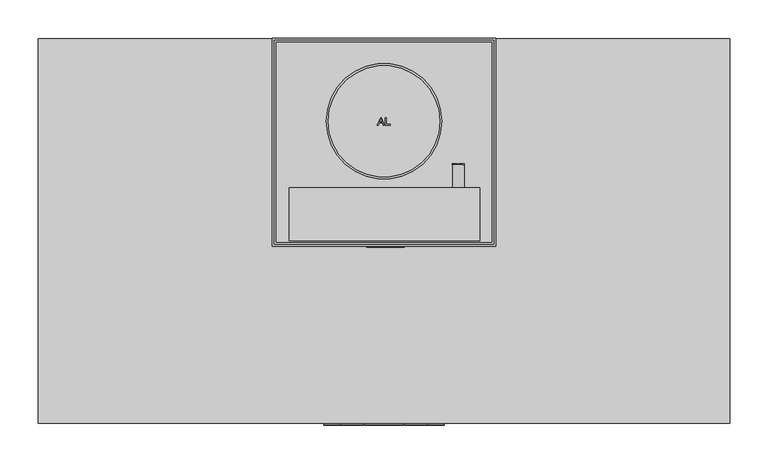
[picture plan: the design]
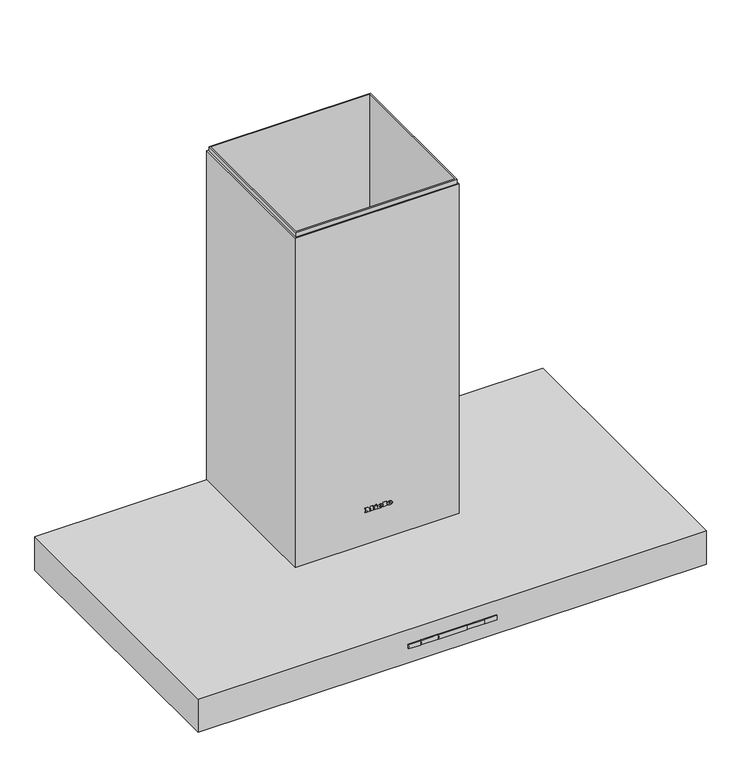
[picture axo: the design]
"""IFC4 building model written with IfcOpenShell, lengths in millimetres: proxy geometry."""

from ifc_helpers import new_model, si_unit, point, frame, frame_2d, origin, place, context, project, spatial, polyline, circle_curve, ellipse_curve, trimmed, segment, composite_curve, outline, extrude, faceted_brep, source, transform, mapped, element, save
from ifc_brep_helpers import plane_surface, cylinder_surface, revolved_surface, extruded_surface, advanced_brep


def specialty_equipment_3feef1e1(model_context):
    return source(origin(), model_context, "Body", "SolidModel", [
        advanced_brep(
        [(-27.2862224, -435.7, 0.8), (27.2862224, -435.7, 0.8), (29.0, -435.7, 2.0), (-29.0, -435.7, 2.0), (0.0, -435.7, 0.8), (0.0, -435.7, 2.0)],
        [
            (0, 1, circle_curve(frame((0.0, -435.7, 0.8), z_axis=(0.0, 0.0, 1.0), x_axis=(1.0, 0.0, 0.0)), 27.2862224)),
            (1, 2),
            (2, 3, circle_curve(frame((0.0, -435.7, 2.0), z_axis=(0.0, 0.0, -1.0), x_axis=(1.0, 0.0, 0.0)), 29.0)),
            (3, 0),
            (1, 0, circle_curve(frame((0.0, -435.7, 0.8), z_axis=(0.0, 0.0, 1.0), x_axis=(1.0, 0.0, 0.0)), 27.2862224)),
            (3, 2, circle_curve(frame((0.0, -435.7, 2.0), z_axis=(0.0, 0.0, -1.0), x_axis=(1.0, 0.0, 0.0)), 29.0)),
            (4, 1),
            (0, 4),
            (2, 5),
            (5, 3),
        ],
        [
            revolved_surface(polyline([(29.0, -435.7, 2.0), (27.2862224, -435.7, 0.8)]), (0.0, -435.7, 1830.7560264), (0.0, 0.0, -1.0)),
            plane_surface(frame((0.0, -435.7, 0.8), z_axis=(0.0, 0.0, -1.0), x_axis=(1.0, 0.0, 0.0))),
            plane_surface(frame((0.0, -435.7, 2.0), z_axis=(0.0, 0.0, 1.0), x_axis=(1.0, 0.0, 0.0))),
        ],
        [
            (0, [[1, 2, 3, 4]]),
            (0, [[5, -4, 6, -2]]),
            (1, [[7, -1, 8]]),
            (1, [[-8, -5, -7]]),
            (2, [[-3, 9, 10]]),
            (2, [[-6, -10, -9]]),
        ],
    ),
        advanced_brep(
        [(-296.5433287, -435.7, 0.8), (-243.4566713, -435.7, 0.8), (-240.883263, -435.7, 2.0), (-299.116737, -435.7, 2.0), (-270.0, -435.7, 0.8), (-270.0, -435.7, 2.0)],
        [
            (0, 1, circle_curve(frame((-270.0, -435.7, 0.8), z_axis=(0.0, 0.0, 1.0), x_axis=(1.0, 0.0, 0.0)), 26.5433287)),
            (1, 2),
            (2, 3, circle_curve(frame((-270.0, -435.7, 2.0), z_axis=(0.0, 0.0, -1.0), x_axis=(1.0, 0.0, 0.0)), 29.116737)),
            (3, 0),
            (1, 0, circle_curve(frame((-270.0, -435.7, 0.8), z_axis=(0.0, 0.0, 1.0), x_axis=(1.0, 0.0, 0.0)), 26.5433287)),
            (3, 2, circle_curve(frame((-270.0, -435.7, 2.0), z_axis=(0.0, 0.0, -1.0), x_axis=(1.0, 0.0, 0.0)), 29.116737)),
            (0, 4),
            (4, 1),
            (2, 5),
            (5, 3),
        ],
        [
            revolved_surface(polyline([(-240.883263, -435.7, 2.0), (-243.4566713, -435.7, 0.8)]), (-270.0, -435.7, 2240.4), (0.0, 0.0, -1.0)),
            plane_surface(frame((-270.0, -435.7, 0.8), z_axis=(0.0, 0.0, -1.0), x_axis=(1.0, 0.0, 0.0))),
            plane_surface(frame((-270.0, -435.7, 2.0), z_axis=(0.0, 0.0, 1.0), x_axis=(1.0, 0.0, 0.0))),
        ],
        [
            (0, [[1, 2, 3, 4]]),
            (0, [[-2, 5, -4, 6]]),
            (1, [[-1, 7, 8]]),
            (1, [[-5, -8, -7]]),
            (2, [[-3, 9, 10]]),
            (2, [[-6, -10, -9]]),
        ],
    ),
        advanced_brep(
        [(243.4566713, -435.7, 0.8), (296.5433287, -435.7, 0.8), (299.116737, -435.7, 2.0), (240.883263, -435.7, 2.0), (270.0, -435.7, 0.8), (270.0, -435.7, 2.0)],
        [
            (0, 1, circle_curve(frame((270.0, -435.7, 0.8), z_axis=(0.0, 0.0, 1.0), x_axis=(1.0, 0.0, 0.0)), 26.5433287)),
            (1, 2),
            (2, 3, circle_curve(frame((270.0, -435.7, 2.0), z_axis=(0.0, 0.0, -1.0), x_axis=(1.0, 0.0, 0.0)), 29.116737)),
            (3, 0),
            (1, 0, circle_curve(frame((270.0, -435.7, 0.8), z_axis=(0.0, 0.0, 1.0), x_axis=(1.0, 0.0, 0.0)), 26.5433287)),
            (3, 2, circle_curve(frame((270.0, -435.7, 2.0), z_axis=(0.0, 0.0, -1.0), x_axis=(1.0, 0.0, 0.0)), 29.116737)),
            (0, 4),
            (4, 1),
            (2, 5),
            (5, 3),
        ],
        [
            revolved_surface(polyline([(299.116737, -435.7, 2.0), (296.5433287, -435.7, 0.8)]), (270.0, -435.7, 2240.4), (0.0, 0.0, -1.0)),
            plane_surface(frame((270.0, -435.7, 0.8), z_axis=(0.0, 0.0, -1.0), x_axis=(1.0, 0.0, 0.0))),
            plane_surface(frame((270.0, -435.7, 2.0), z_axis=(0.0, 0.0, 1.0), x_axis=(1.0, 0.0, 0.0))),
        ],
        [
            (0, [[1, 2, 3, 4]]),
            (0, [[-2, 5, -4, 6]]),
            (1, [[-1, 7, 8]]),
            (1, [[-5, -8, -7]]),
            (2, [[-3, 9, 10]]),
            (2, [[-6, -10, -9]]),
        ],
    ),
        extrude(outline(polyline([(134.3333333, -34.0), (134.3333333, -391.0), (-134.3333333, -391.0), (-134.3333333, -34.0), (134.3333333, -34.0)])), frame((0.0, 0.0, 6.5), z_axis=(0.0, 0.0, 1.0), x_axis=(1.0, 0.0, 0.0)), (0.0, 0.0, 1.0), 6.0),
        extrude(outline(polyline([(143.3333333, -25.0), (143.3333333, -400.0), (-143.3333333, -400.0), (-143.3333333, -25.0), (143.3333333, -25.0)]), holes=[polyline([(134.3333333, -34.0), (-134.3333333, -34.0), (-134.3333333, -391.0), (134.3333333, -391.0), (134.3333333, -34.0)])]), frame((0.0, 0.0, 5.0), z_axis=(0.0, 0.0, 1.0), x_axis=(1.0, 0.0, 0.0)), (0.0, 0.0, 1.0), 9.0),
        extrude(outline(polyline([(152.3333333, -34.0), (421.0, -34.0), (421.0, -391.0), (152.3333333, -391.0), (152.3333333, -34.0)])), frame((0.0, 0.0, 6.5), z_axis=(0.0, 0.0, 1.0), x_axis=(1.0, 0.0, 0.0)), (0.0, 0.0, 1.0), 6.0),
        extrude(outline(polyline([(143.3333333, -25.0), (430.0, -25.0), (430.0, -400.0), (143.3333333, -400.0), (143.3333333, -25.0)]), holes=[polyline([(152.3333333, -34.0), (152.3333333, -391.0), (421.0, -391.0), (421.0, -34.0), (152.3333333, -34.0)])]), frame((0.0, 0.0, 5.0), z_axis=(0.0, 0.0, 1.0), x_axis=(1.0, 0.0, 0.0)), (0.0, 0.0, 1.0), 9.0),
        extrude(outline(polyline([(-152.3333333, -34.0), (-152.3333333, -391.0), (-421.0, -391.0), (-421.0, -34.0), (-152.3333333, -34.0)])), frame((0.0, 0.0, 6.5), z_axis=(0.0, 0.0, 1.0), x_axis=(1.0, 0.0, 0.0)), (0.0, 0.0, 1.0), 6.0),
        extrude(outline(polyline([(-143.3333333, -25.0), (-143.3333333, -400.0), (-430.0, -400.0), (-430.0, -25.0), (-143.3333333, -25.0)]), holes=[polyline([(-152.3333333, -34.0), (-421.0, -34.0), (-421.0, -391.0), (-152.3333333, -391.0), (-152.3333333, -34.0)])]), frame((0.0, 0.0, 5.0), z_axis=(0.0, 0.0, 1.0), x_axis=(1.0, 0.0, 0.0)), (0.0, 0.0, 1.0), 9.0),
        extrude(outline(polyline([(16.5, -348.0), (16.5, -391.0), (-16.5, -391.0), (-16.5, -348.0), (16.5, -348.0)]), holes=[polyline([(10.0, -354.5), (-10.0, -354.5), (-10.0, -363.5), (10.0, -363.5), (10.0, -354.5)])]), frame((0.0, 0.0, 5.0), z_axis=(0.0, 0.0, 1.0), x_axis=(1.0, 0.0, 0.0)), (0.0, 0.0, 1.0), 1.5),
        extrude(outline(polyline([(270.1666667, -348.0), (303.1666667, -348.0), (303.1666667, -391.0), (270.1666667, -391.0), (270.1666667, -348.0)]), holes=[polyline([(276.6666667, -354.5), (276.6666667, -363.5), (296.4380995, -363.5), (296.4380995, -354.5), (276.6666667, -354.5)])]), frame((0.0, 0.0, 5.0), z_axis=(0.0, 0.0, 1.0), x_axis=(1.0, 0.0, 0.0)), (0.0, 0.0, 1.0), 1.5),
        extrude(outline(polyline([(-270.1666667, -348.0), (-270.1666667, -391.0), (-303.1666667, -391.0), (-303.1666667, -348.0), (-270.1666667, -348.0)]), holes=[polyline([(-276.6666667, -354.5), (-296.6666667, -354.5), (-296.6666667, -363.5), (-276.6666667, -363.5), (-276.6666667, -354.5)])]), frame((0.0, 0.0, 5.0), z_axis=(0.0, 0.0, 1.0), x_axis=(1.0, 0.0, 0.0)), (0.0, 0.0, 1.0), 1.5),
        faceted_brep([(-142.5, -267.5, 685.0), (142.5, -267.5, 685.0), (142.5, -2.5, 685.0), (-142.5, -2.5, 685.0), (140.0, -5.0, 685.0), (140.0, -265.0, 685.0), (-140.0, -265.0, 685.0), (-140.0, -5.0, 685.0), (-142.5, -267.5, 210.0), (-142.5, -2.5, 210.0), (142.5, -2.5, 210.0), (142.5, -267.5, 210.0), (140.0, -5.0, 210.0), (-140.0, -5.0, 210.0), (-140.0, -265.0, 210.0), (140.0, -265.0, 210.0), (-142.5, -247.0, 245.0), (-142.5, -236.4, 245.0), (-142.5, -236.4, 345.0), (-142.5, -247.0, 345.0), (-142.5, -225.8, 245.0), (-142.5, -215.2, 245.0), (-142.5, -215.2, 345.0), (-142.5, -225.8, 345.0), (-142.5, -204.6, 245.0), (-142.5, -194.0, 245.0), (-142.5, -194.0, 345.0), (-142.5, -204.6, 345.0), (-142.5, -183.4, 245.0), (-142.5, -172.8, 245.0), (-142.5, -172.8, 345.0), (-142.5, -183.4, 345.0), (-142.5, -162.2, 245.0), (-142.5, -151.6, 245.0), (-142.5, -151.6, 345.0), (-142.5, -162.2, 345.0), (-142.5, -141.0, 245.0), (-142.5, -129.0, 245.0), (-142.5, -129.0, 345.0), (-142.5, -141.0, 345.0), (-142.5, -118.4, 245.0), (-142.5, -107.8, 245.0), (-142.5, -107.8, 345.0), (-142.5, -118.4, 345.0), (-142.5, -97.2, 245.0), (-142.5, -86.6, 245.0), (-142.5, -86.6, 345.0), (-142.5, -97.2, 345.0), (-142.5, -76.0, 245.0), (-142.5, -65.4, 245.0), (-142.5, -65.4, 345.0), (-142.5, -76.0, 345.0), (-142.5, -54.8, 245.0), (-142.5, -44.2, 245.0), (-142.5, -44.2, 345.0), (-142.5, -54.8, 345.0), (-142.5, -33.6, 245.0), (-142.5, -23.0, 245.0), (-142.5, -23.0, 345.0), (-142.5, -33.6, 345.0), (121.0, -265.0, 245.0), (121.0, -265.0, 345.0), (109.0, -265.0, 345.0), (109.0, -265.0, 245.0), (-121.0, -265.0, 345.0), (-121.0, -265.0, 245.0), (-109.0, -265.0, 245.0), (-109.0, -265.0, 345.0), (-86.0, -265.0, 345.0), (-97.5, -265.0, 345.0), (-97.5, -265.0, 245.0), (-86.0, -265.0, 245.0), (-63.0, -265.0, 345.0), (-74.5, -265.0, 345.0), (-74.5, -265.0, 245.0), (-63.0, -265.0, 245.0), (-40.0, -265.0, 345.0), (-51.5, -265.0, 345.0), (-51.5, -265.0, 245.0), (-40.0, -265.0, 245.0), (-17.0, -265.0, 345.0), (-28.5, -265.0, 345.0), (-28.5, -265.0, 245.0), (-17.0, -265.0, 245.0), (5.5, -265.0, 345.0), (-5.5, -265.0, 345.0), (-5.5, -265.0, 245.0), (5.5, -265.0, 245.0), (28.5, -265.0, 345.0), (17.0, -265.0, 345.0), (17.0, -265.0, 245.0), (28.5, -265.0, 245.0), (51.5, -265.0, 345.0), (40.0, -265.0, 345.0), (40.0, -265.0, 245.0), (51.5, -265.0, 245.0), (74.5, -265.0, 345.0), (63.0, -265.0, 345.0), (63.0, -265.0, 245.0), (74.5, -265.0, 245.0), (97.5, -265.0, 345.0), (86.0, -265.0, 345.0), (86.0, -265.0, 245.0), (97.5, -265.0, 245.0), (-140.0, -236.4, 245.0), (-140.0, -247.0, 245.0), (-140.0, -247.0, 345.0), (-140.0, -236.4, 345.0), (-140.0, -215.2, 245.0), (-140.0, -225.8, 245.0), (-140.0, -225.8, 345.0), (-140.0, -215.2, 345.0), (-140.0, -194.0, 245.0), (-140.0, -204.6, 245.0), (-140.0, -204.6, 345.0), (-140.0, -194.0, 345.0), (-140.0, -172.8, 245.0), (-140.0, -183.4, 245.0), (-140.0, -183.4, 345.0), (-140.0, -172.8, 345.0), (-140.0, -151.6, 245.0), (-140.0, -162.2, 245.0), (-140.0, -162.2, 345.0), (-140.0, -151.6, 345.0), (-140.0, -129.0, 245.0), (-140.0, -141.0, 245.0), (-140.0, -141.0, 345.0), (-140.0, -129.0, 345.0), (-140.0, -107.8, 245.0), (-140.0, -118.4, 245.0), (-140.0, -118.4, 345.0), (-140.0, -107.8, 345.0), (-140.0, -86.6, 245.0), (-140.0, -97.2, 245.0), (-140.0, -97.2, 345.0), (-140.0, -86.6, 345.0), (-140.0, -65.4, 245.0), (-140.0, -76.0, 245.0), (-140.0, -76.0, 345.0), (-140.0, -65.4, 345.0), (-140.0, -44.2, 245.0), (-140.0, -54.8, 245.0), (-140.0, -54.8, 345.0), (-140.0, -44.2, 345.0), (-140.0, -23.0, 245.0), (-140.0, -33.6, 245.0), (-140.0, -33.6, 345.0), (-140.0, -23.0, 345.0), (140.0, -247.0, 345.0), (140.0, -247.0, 245.0), (140.0, -236.4, 245.0), (140.0, -236.4, 345.0), (140.0, -23.0, 245.0), (140.0, -23.0, 345.0), (140.0, -33.6, 345.0), (140.0, -33.6, 245.0), (140.0, -225.8, 345.0), (140.0, -225.8, 245.0), (140.0, -215.2, 245.0), (140.0, -215.2, 345.0), (140.0, -204.6, 345.0), (140.0, -204.6, 245.0), (140.0, -194.0, 245.0), (140.0, -194.0, 345.0), (140.0, -183.4, 345.0), (140.0, -183.4, 245.0), (140.0, -172.8, 245.0), (140.0, -172.8, 345.0), (140.0, -162.2, 345.0), (140.0, -162.2, 245.0), (140.0, -151.6, 245.0), (140.0, -151.6, 345.0), (140.0, -44.2, 245.0), (140.0, -44.2, 345.0), (140.0, -54.8, 345.0), (140.0, -54.8, 245.0), (140.0, -65.4, 245.0), (140.0, -65.4, 345.0), (140.0, -76.0, 345.0), (140.0, -76.0, 245.0), (140.0, -86.6, 245.0), (140.0, -86.6, 345.0), (140.0, -97.2, 345.0), (140.0, -97.2, 245.0), (140.0, -107.8, 245.0), (140.0, -107.8, 345.0), (140.0, -118.4, 345.0), (140.0, -118.4, 245.0), (140.0, -129.0, 245.0), (140.0, -129.0, 345.0), (140.0, -141.0, 345.0), (140.0, -141.0, 245.0), (142.5, -23.0, 345.0), (142.5, -23.0, 245.0), (142.5, -33.6, 245.0), (142.5, -33.6, 345.0), (142.5, -247.0, 245.0), (142.5, -247.0, 345.0), (142.5, -236.4, 345.0), (142.5, -236.4, 245.0), (142.5, -225.8, 245.0), (142.5, -225.8, 345.0), (142.5, -215.2, 345.0), (142.5, -215.2, 245.0), (142.5, -204.6, 245.0), (142.5, -204.6, 345.0), (142.5, -194.0, 345.0), (142.5, -194.0, 245.0), (142.5, -183.4, 245.0), (142.5, -183.4, 345.0), (142.5, -172.8, 345.0), (142.5, -172.8, 245.0), (142.5, -162.2, 245.0), (142.5, -162.2, 345.0), (142.5, -151.6, 345.0), (142.5, -151.6, 245.0), (142.5, -44.2, 345.0), (142.5, -44.2, 245.0), (142.5, -54.8, 245.0), (142.5, -54.8, 345.0), (142.5, -65.4, 345.0), (142.5, -65.4, 245.0), (142.5, -76.0, 245.0), (142.5, -76.0, 345.0), (142.5, -86.6, 345.0), (142.5, -86.6, 245.0), (142.5, -97.2, 245.0), (142.5, -97.2, 345.0), (142.5, -107.8, 345.0), (142.5, -107.8, 245.0), (142.5, -118.4, 245.0), (142.5, -118.4, 345.0), (142.5, -129.0, 345.0), (142.5, -129.0, 245.0), (142.5, -141.0, 245.0), (142.5, -141.0, 345.0), (121.0, -267.5, 345.0), (121.0, -267.5, 245.0), (109.0, -267.5, 245.0), (109.0, -267.5, 345.0), (-121.0, -267.5, 245.0), (-121.0, -267.5, 345.0), (-109.0, -267.5, 345.0), (-109.0, -267.5, 245.0), (-97.5, -267.5, 345.0), (-86.0, -267.5, 345.0), (-86.0, -267.5, 245.0), (-97.5, -267.5, 245.0), (-74.5, -267.5, 345.0), (-63.0, -267.5, 345.0), (-63.0, -267.5, 245.0), (-74.5, -267.5, 245.0), (-51.5, -267.5, 345.0), (-40.0, -267.5, 345.0), (-40.0, -267.5, 245.0), (-51.5, -267.5, 245.0), (-28.5, -267.5, 345.0), (-17.0, -267.5, 345.0), (-17.0, -267.5, 245.0), (-28.5, -267.5, 245.0), (-5.5, -267.5, 345.0), (5.5, -267.5, 345.0), (5.5, -267.5, 245.0), (-5.5, -267.5, 245.0), (17.0, -267.5, 345.0), (28.5, -267.5, 345.0), (28.5, -267.5, 245.0), (17.0, -267.5, 245.0), (40.0, -267.5, 345.0), (51.5, -267.5, 345.0), (51.5, -267.5, 245.0), (40.0, -267.5, 245.0), (63.0, -267.5, 345.0), (74.5, -267.5, 345.0), (74.5, -267.5, 245.0), (63.0, -267.5, 245.0), (86.0, -267.5, 345.0), (97.5, -267.5, 345.0), (97.5, -267.5, 245.0), (86.0, -267.5, 245.0)], [[[0, 1, 2, 3], [4, 5, 6, 7]], [[8, 9, 10, 11], [12, 13, 14, 15]], [[0, 3, 9, 8], [16, 17, 18, 19], [20, 21, 22, 23], [24, 25, 26, 27], [28, 29, 30, 31], [32, 33, 34, 35], [36, 37, 38, 39], [40, 41, 42, 43], [44, 45, 46, 47], [48, 49, 50, 51], [52, 53, 54, 55], [56, 57, 58, 59]], [[6, 5, 15, 14], [60, 61, 62, 63], [64, 65, 66, 67], [68, 69, 70, 71], [72, 73, 74, 75], [76, 77, 78, 79], [80, 81, 82, 83], [84, 85, 86, 87], [88, 89, 90, 91], [92, 93, 94, 95], [96, 97, 98, 99], [100, 101, 102, 103]], [[7, 6, 14, 13], [104, 105, 106, 107], [108, 109, 110, 111], [112, 113, 114, 115], [116, 117, 118, 119], [120, 121, 122, 123], [124, 125, 126, 127], [128, 129, 130, 131], [132, 133, 134, 135], [136, 137, 138, 139], [140, 141, 142, 143], [144, 145, 146, 147]], [[5, 4, 12, 15], [148, 149, 150, 151], [152, 153, 154, 155], [156, 157, 158, 159], [160, 161, 162, 163], [164, 165, 166, 167], [168, 169, 170, 171], [172, 173, 174, 175], [176, 177, 178, 179], [180, 181, 182, 183], [184, 185, 186, 187], [188, 189, 190, 191]], [[2, 1, 11, 10], [192, 193, 194, 195], [196, 197, 198, 199], [200, 201, 202, 203], [204, 205, 206, 207], [208, 209, 210, 211], [212, 213, 214, 215], [216, 217, 218, 219], [220, 221, 222, 223], [224, 225, 226, 227], [228, 229, 230, 231], [232, 233, 234, 235]], [[1, 0, 8, 11], [236, 237, 238, 239], [240, 241, 242, 243], [244, 245, 246, 247], [248, 249, 250, 251], [252, 253, 254, 255], [256, 257, 258, 259], [260, 261, 262, 263], [264, 265, 266, 267], [268, 269, 270, 271], [272, 273, 274, 275], [276, 277, 278, 279]], [[3, 2, 10, 9]], [[4, 7, 13, 12]], [[60, 237, 236, 61]], [[64, 241, 240, 65]], [[196, 149, 148, 197]], [[192, 153, 152, 193]], [[149, 196, 199, 150]], [[150, 199, 198, 151]], [[197, 148, 151, 198]], [[153, 192, 195, 154]], [[154, 195, 194, 155]], [[193, 152, 155, 194]], [[200, 157, 156, 201]], [[157, 200, 203, 158]], [[158, 203, 202, 159]], [[201, 156, 159, 202]], [[204, 161, 160, 205]], [[161, 204, 207, 162]], [[162, 207, 206, 163]], [[205, 160, 163, 206]], [[208, 165, 164, 209]], [[165, 208, 211, 166]], [[166, 211, 210, 167]], [[209, 164, 167, 210]], [[212, 169, 168, 213]], [[169, 212, 215, 170]], [[170, 215, 214, 171]], [[213, 168, 171, 214]], [[216, 173, 172, 217]], [[173, 216, 219, 174]], [[174, 219, 218, 175]], [[217, 172, 175, 218]], [[220, 177, 176, 221]], [[177, 220, 223, 178]], [[178, 223, 222, 179]], [[221, 176, 179, 222]], [[224, 181, 180, 225]], [[181, 224, 227, 182]], [[182, 227, 226, 183]], [[225, 180, 183, 226]], [[228, 185, 184, 229]], [[185, 228, 231, 186]], [[186, 231, 230, 187]], [[229, 184, 187, 230]], [[232, 189, 188, 233]], [[189, 232, 235, 190]], [[190, 235, 234, 191]], [[233, 188, 191, 234]], [[104, 17, 16, 105]], [[17, 104, 107, 18]], [[18, 107, 106, 19]], [[105, 16, 19, 106]], [[108, 21, 20, 109]], [[21, 108, 111, 22]], [[22, 111, 110, 23]], [[109, 20, 23, 110]], [[112, 25, 24, 113]], [[25, 112, 115, 26]], [[26, 115, 114, 27]], [[113, 24, 27, 114]], [[116, 29, 28, 117]], [[29, 116, 119, 30]], [[30, 119, 118, 31]], [[117, 28, 31, 118]], [[120, 33, 32, 121]], [[33, 120, 123, 34]], [[34, 123, 122, 35]], [[121, 32, 35, 122]], [[124, 37, 36, 125]], [[37, 124, 127, 38]], [[38, 127, 126, 39]], [[125, 36, 39, 126]], [[128, 41, 40, 129]], [[41, 128, 131, 42]], [[42, 131, 130, 43]], [[129, 40, 43, 130]], [[132, 45, 44, 133]], [[45, 132, 135, 46]], [[46, 135, 134, 47]], [[133, 44, 47, 134]], [[136, 49, 48, 137]], [[49, 136, 139, 50]], [[50, 139, 138, 51]], [[137, 48, 51, 138]], [[140, 53, 52, 141]], [[53, 140, 143, 54]], [[54, 143, 142, 55]], [[141, 52, 55, 142]], [[144, 57, 56, 145]], [[57, 144, 147, 58]], [[58, 147, 146, 59]], [[145, 56, 59, 146]], [[241, 64, 67, 242]], [[242, 67, 66, 243]], [[65, 240, 243, 66]], [[237, 60, 63, 238]], [[238, 63, 62, 239]], [[61, 236, 239, 62]], [[68, 245, 244, 69]], [[245, 68, 71, 246]], [[246, 71, 70, 247]], [[69, 244, 247, 70]], [[72, 249, 248, 73]], [[249, 72, 75, 250]], [[250, 75, 74, 251]], [[73, 248, 251, 74]], [[76, 253, 252, 77]], [[253, 76, 79, 254]], [[254, 79, 78, 255]], [[77, 252, 255, 78]], [[80, 257, 256, 81]], [[257, 80, 83, 258]], [[258, 83, 82, 259]], [[81, 256, 259, 82]], [[84, 261, 260, 85]], [[261, 84, 87, 262]], [[262, 87, 86, 263]], [[85, 260, 263, 86]], [[88, 265, 264, 89]], [[265, 88, 91, 266]], [[266, 91, 90, 267]], [[89, 264, 267, 90]], [[92, 269, 268, 93]], [[269, 92, 95, 270]], [[270, 95, 94, 271]], [[93, 268, 271, 94]], [[96, 273, 272, 97]], [[273, 96, 99, 274]], [[274, 99, 98, 275]], [[97, 272, 275, 98]], [[100, 277, 276, 101]], [[277, 100, 103, 278]], [[278, 103, 102, 279]], [[101, 276, 279, 102]]]),
        extrude(outline(polyline([(145.0, 0.0), (145.0, -270.0), (-145.0, -270.0), (-145.0, 0.0), (145.0, 0.0)]), holes=[polyline([(-142.5, -2.5), (-142.5, -267.5), (142.5, -267.5), (142.5, -2.5), (-142.5, -2.5)])]), frame((0.0, 0.0, 62.0), z_axis=(0.0, 0.0, 1.0), x_axis=(1.0, 0.0, 0.0)), (0.0, 0.0, 1.0), 615.0),
        advanced_brep(
        [(21.104, -271.0, 123.896), (21.104, -271.0, 124.704), (26.456, -271.0, 124.704), (17.144, -271.0, 124.704), (19.344, -271.0, 122.0), (26.32, -271.0, 123.896), (23.904, -271.0, 123.896), (22.0, -271.0, 123.0), (21.104, -271.0, 125.728), (21.104, -271.0, 126.6), (22.472, -271.0, 126.6), (22.472, -271.0, 125.728), (21.104, -270.0, 123.896), (22.0, -270.0, 123.0), (23.904, -270.0, 123.896), (26.32, -270.0, 123.896), (19.344, -270.0, 122.0), (17.144, -270.0, 124.704), (26.456, -270.0, 124.704), (21.104, -270.0, 124.704), (21.104, -270.0, 125.728), (22.472, -270.0, 125.728), (22.472, -270.0, 126.6), (21.104, -270.0, 126.6)],
        [
            (0, 1),
            (1, 2),
            (2, 3, ellipse_curve(frame((21.8, -271.0, 124.704), z_axis=(0.0, -1.0, -1.2192856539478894e-11), x_axis=(-1.0, 0.0, 0.0)), 4.656, 3.848)),
            (3, 4, circle_curve(frame((20.2400436, -271.0, 124.976), z_axis=(0.0, -1.0, -1.2192856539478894e-11), x_axis=(0.0, 1.2192856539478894e-11, -1.0)), 3.1079688)),
            (4, 5, circle_curve(frame((21.7067936, -271.0, 127.088), z_axis=(0.0, -1.0, -1.2192856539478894e-11), x_axis=(0.0, 1.2192856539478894e-11, -1.0)), 5.6098607)),
            (5, 6),
            (6, 7, circle_curve(frame((22.3910588, -271.0, 124.64), z_axis=(0.0, 1.0, 1.2192856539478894e-11), x_axis=(0.0, 1.2192856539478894e-11, -1.0)), 1.6859795)),
            (7, 0, circle_curve(frame((22.0, -271.0, 123.896), z_axis=(0.0, 1.0, 1.2192856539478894e-11), x_axis=(0.0, 1.2192856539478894e-11, -1.0)), 0.896)),
            (8, 9),
            (9, 10, circle_curve(frame((21.788, -271.0, 126.6), z_axis=(0.0, 1.0, 1.2192856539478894e-11), x_axis=(0.0, 1.2192856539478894e-11, -1.0)), 0.684)),
            (10, 11),
            (11, 8),
            (12, 13, circle_curve(frame((22.0, -270.0, 123.896), z_axis=(0.0, -1.0, -1.2192856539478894e-11), x_axis=(0.0, 1.2192856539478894e-11, -1.0)), 0.896)),
            (13, 14, circle_curve(frame((22.3910588, -270.0, 124.64), z_axis=(0.0, -1.0, -1.2192856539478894e-11), x_axis=(0.0, 1.2192856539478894e-11, -1.0)), 1.6859795)),
            (14, 15),
            (15, 16, circle_curve(frame((21.7067936, -270.0, 127.088), z_axis=(0.0, 1.0, 1.2192856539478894e-11), x_axis=(0.0, 1.2192856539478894e-11, -1.0)), 5.6098607)),
            (16, 17, circle_curve(frame((20.2400436, -270.0, 124.976), z_axis=(0.0, 1.0, 1.2192856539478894e-11), x_axis=(0.0, 1.2192856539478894e-11, -1.0)), 3.1079688)),
            (17, 18, ellipse_curve(frame((21.8, -270.0, 124.704), z_axis=(0.0, 1.0, 1.2192856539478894e-11), x_axis=(-1.0, 0.0, 0.0)), 4.656, 3.848)),
            (18, 19),
            (19, 12),
            (20, 21),
            (21, 22),
            (22, 23, circle_curve(frame((21.788, -270.0, 126.6), z_axis=(0.0, -1.0, -1.2192856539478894e-11), x_axis=(0.0, 1.2192856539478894e-11, -1.0)), 0.684)),
            (23, 20),
            (0, 12),
            (19, 1),
            (18, 2),
            (5, 15),
            (14, 6),
            (17, 3),
            (13, 7),
            (16, 4),
            (8, 20),
            (23, 9),
            (22, 10),
            (21, 11),
        ],
        [
            plane_surface(frame((21.104, -271.0, 124.704), z_axis=(0.0, -1.0, -1.2192856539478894e-11), x_axis=(0.0, -1.2192856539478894e-11, 1.0))),
            plane_surface(frame((21.104, -270.0, 124.704), z_axis=(0.0, 1.0, 1.2192856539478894e-11), x_axis=(0.0, 1.2192856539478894e-11, -1.0))),
            plane_surface(frame((21.104, -271.0, 123.896), z_axis=(1.0, 0.0, 0.0), x_axis=(0.0, 1.0, 1.2192856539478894e-11))),
            plane_surface(frame((21.104, -271.0, 124.704), z_axis=(0.0, 1.2192856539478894e-11, -1.0), x_axis=(0.0, 1.0, 1.2192856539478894e-11))),
            plane_surface(frame((26.32, -271.0, 123.896), z_axis=(0.0, -1.2192856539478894e-11, 1.0), x_axis=(0.0, 1.0, 1.2192856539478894e-11))),
            extruded_surface(trimmed(ellipse_curve(frame((21.8, -269.0, 124.704), z_axis=(0.0, -1.0, -1.2192856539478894e-11), x_axis=(-1.0, 0.0, 0.0)), 4.656, 3.848), [point((26.456, -269.0, 124.704))], [point((17.144, -269.0, 124.704))], True, "CARTESIAN"), (0.0, -1.0, 0.0), 1.0),
            revolved_surface(polyline([(22.3910588, -269.9999999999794, 122.9540205), (22.3910588, -270.99999999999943, 122.9540204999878)]), (22.3910588, -270.0, 124.64), (0.0, 1.0, 1.2192856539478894e-11)),
            revolved_surface(polyline([(22.0, -269.9999999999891, 123.0), (22.0, -271.0, 122.9999999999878)]), (22.0, -270.0, 123.896), (0.0, 1.0, 1.2192856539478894e-11)),
            cylinder_surface(frame((20.2400436, -270.0, 124.976), z_axis=(0.0, -1.0, -1.2192856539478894e-11), x_axis=(0.0, 1.2192856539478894e-11, -1.0)), 3.1079688),
            cylinder_surface(frame((21.7067936, -270.0, 127.088), z_axis=(0.0, -1.0, -1.2192856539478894e-11), x_axis=(0.0, 1.2192856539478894e-11, -1.0)), 5.6098607),
            plane_surface(frame((21.104, -271.0, 125.728), z_axis=(1.0, 0.0, 0.0), x_axis=(0.0, 1.0, 1.2192856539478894e-11))),
            revolved_surface(polyline([(21.788, -269.99999999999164, 125.916), (21.788, -270.99999999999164, 125.9159999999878)]), (21.788, -270.0, 126.6), (0.0, 1.0, 1.2192856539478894e-11)),
            plane_surface(frame((22.472, -271.0, 126.6), z_axis=(-1.0, 0.0, 0.0), x_axis=(0.0, 1.0, 1.2192856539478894e-11))),
            plane_surface(frame((22.472, -271.0, 125.728), z_axis=(0.0, -1.2192856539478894e-11, 1.0), x_axis=(0.0, 1.0, 1.2192856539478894e-11))),
        ],
        [
            (0, [[1, 2, 3, 4, 5, 6, 7, 8], [9, 10, 11, 12]]),
            (1, [[13, 14, 15, 16, 17, 18, 19, 20], [21, 22, 23, 24]]),
            (2, [[-1, 25, -20, 26]]),
            (3, [[-2, -26, -19, 27]]),
            (4, [[-6, 28, -15, 29]]),
            (5, [[-3, -27, -18, 30]]),
            (6, [[-7, -29, -14, 31]]),
            (7, [[-8, -31, -13, -25]]),
            (8, [[-4, -30, -17, 32]]),
            (9, [[-5, -32, -16, -28]]),
            (10, [[-9, 33, -24, 34]]),
            (11, [[-10, -34, -23, 35]]),
            (12, [[-11, -35, -22, 36]]),
            (13, [[-12, -36, -21, -33]]),
        ],
    ),
        advanced_brep(
        [(4.408, -271.0, 123.896), (4.408, -271.0, 124.704), (9.76, -271.0, 124.704), (0.448, -271.0, 124.704), (2.648, -271.0, 122.0), (9.624, -271.0, 123.896), (7.208, -271.0, 123.896), (5.304, -271.0, 123.0), (4.408, -271.0, 125.728), (4.408, -271.0, 126.6), (5.776, -271.0, 126.6), (5.776, -271.0, 125.728), (4.408, -270.0, 123.896), (5.304, -270.0, 123.0), (7.208, -270.0, 123.896), (9.624, -270.0, 123.896), (2.648, -270.0, 122.0), (0.448, -270.0, 124.704), (9.76, -270.0, 124.704), (4.408, -270.0, 124.704), (4.408, -270.0, 125.728), (5.776, -270.0, 125.728), (5.776, -270.0, 126.6), (4.408, -270.0, 126.6)],
        [
            (0, 1),
            (1, 2),
            (2, 3, ellipse_curve(frame((5.104, -271.0, 124.704), z_axis=(0.0, -1.0, -1.2192856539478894e-11), x_axis=(-1.0, 0.0, 0.0)), 4.656, 3.848)),
            (3, 4, circle_curve(frame((3.5440436, -271.0, 124.976), z_axis=(0.0, -1.0, -1.2192856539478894e-11), x_axis=(0.0, 1.2192856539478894e-11, -1.0)), 3.1079688)),
            (4, 5, circle_curve(frame((5.0107936, -271.0, 127.088), z_axis=(0.0, -1.0, -1.2192856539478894e-11), x_axis=(0.0, 1.2192856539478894e-11, -1.0)), 5.6098607)),
            (5, 6),
            (6, 7, circle_curve(frame((5.6950588, -271.0, 124.64), z_axis=(0.0, 1.0, 1.2192856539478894e-11), x_axis=(0.0, 1.2192856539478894e-11, -1.0)), 1.6859795)),
            (7, 0, circle_curve(frame((5.304, -271.0, 123.896), z_axis=(0.0, 1.0, 1.2192856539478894e-11), x_axis=(0.0, 1.2192856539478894e-11, -1.0)), 0.896)),
            (8, 9),
            (9, 10, circle_curve(frame((5.092, -271.0, 126.6), z_axis=(0.0, 1.0, 1.2192856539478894e-11), x_axis=(0.0, 1.2192856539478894e-11, -1.0)), 0.684)),
            (10, 11),
            (11, 8),
            (12, 13, circle_curve(frame((5.304, -270.0, 123.896), z_axis=(0.0, -1.0, -1.2192856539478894e-11), x_axis=(0.0, 1.2192856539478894e-11, -1.0)), 0.896)),
            (13, 14, circle_curve(frame((5.6950588, -270.0, 124.64), z_axis=(0.0, -1.0, -1.2192856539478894e-11), x_axis=(0.0, 1.2192856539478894e-11, -1.0)), 1.6859795)),
            (14, 15),
            (15, 16, circle_curve(frame((5.0107936, -270.0, 127.088), z_axis=(0.0, 1.0, 1.2192856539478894e-11), x_axis=(0.0, 1.2192856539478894e-11, -1.0)), 5.6098607)),
            (16, 17, circle_curve(frame((3.5440436, -270.0, 124.976), z_axis=(0.0, 1.0, 1.2192856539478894e-11), x_axis=(0.0, 1.2192856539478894e-11, -1.0)), 3.1079688)),
            (17, 18, ellipse_curve(frame((5.104, -270.0, 124.704), z_axis=(0.0, 1.0, 1.2192856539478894e-11), x_axis=(-1.0, 0.0, 0.0)), 4.656, 3.848)),
            (18, 19),
            (19, 12),
            (20, 21),
            (21, 22),
            (22, 23, circle_curve(frame((5.092, -270.0, 126.6), z_axis=(0.0, -1.0, -1.2192856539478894e-11), x_axis=(0.0, 1.2192856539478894e-11, -1.0)), 0.684)),
            (23, 20),
            (0, 12),
            (19, 1),
            (18, 2),
            (5, 15),
            (14, 6),
            (17, 3),
            (13, 7),
            (16, 4),
            (8, 20),
            (23, 9),
            (22, 10),
            (21, 11),
        ],
        [
            plane_surface(frame((4.408, -271.0, 124.704), z_axis=(0.0, -1.0, -1.2192856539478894e-11), x_axis=(0.0, -1.2192856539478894e-11, 1.0))),
            plane_surface(frame((4.408, -270.0, 124.704), z_axis=(0.0, 1.0, 1.2192856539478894e-11), x_axis=(0.0, 1.2192856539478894e-11, -1.0))),
            plane_surface(frame((4.408, -271.0, 123.896), z_axis=(1.0, 0.0, 0.0), x_axis=(0.0, 1.0, 1.2192856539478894e-11))),
            plane_surface(frame((4.408, -271.0, 124.704), z_axis=(0.0, 1.2192856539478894e-11, -1.0), x_axis=(0.0, 1.0, 1.2192856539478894e-11))),
            plane_surface(frame((9.624, -271.0, 123.896), z_axis=(0.0, -1.2192856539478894e-11, 1.0), x_axis=(0.0, 1.0, 1.2192856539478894e-11))),
            extruded_surface(trimmed(ellipse_curve(frame((5.104, -269.0, 124.704), z_axis=(0.0, -1.0, -1.2192856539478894e-11), x_axis=(-1.0, 0.0, 0.0)), 4.656, 3.848), [point((9.76, -269.0, 124.704))], [point((0.448, -269.0, 124.704))], True, "CARTESIAN"), (0.0, -1.0, 0.0), 1.0),
            revolved_surface(polyline([(5.6950588, -269.9999999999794, 122.9540205), (5.6950588, -270.99999999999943, 122.9540204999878)]), (5.6950588, -270.0, 124.64), (0.0, 1.0, 1.2192856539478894e-11)),
            revolved_surface(polyline([(5.304, -269.9999999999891, 123.0), (5.304, -271.0, 122.9999999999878)]), (5.304, -270.0, 123.896), (0.0, 1.0, 1.2192856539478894e-11)),
            cylinder_surface(frame((3.5440436, -270.0, 124.976), z_axis=(0.0, -1.0, -1.2192856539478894e-11), x_axis=(0.0, 1.2192856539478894e-11, -1.0)), 3.1079688),
            cylinder_surface(frame((5.0107936, -270.0, 127.088), z_axis=(0.0, -1.0, -1.2192856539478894e-11), x_axis=(0.0, 1.2192856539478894e-11, -1.0)), 5.6098607),
            plane_surface(frame((4.408, -271.0, 125.728), z_axis=(1.0, 0.0, 0.0), x_axis=(0.0, 1.0, 1.2192856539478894e-11))),
            revolved_surface(polyline([(5.092, -269.99999999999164, 125.916), (5.092, -270.99999999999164, 125.9159999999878)]), (5.092, -270.0, 126.6), (0.0, 1.0, 1.2192856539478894e-11)),
            plane_surface(frame((5.776, -271.0, 126.6), z_axis=(-1.0, 0.0, 0.0), x_axis=(0.0, 1.0, 1.2192856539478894e-11))),
            plane_surface(frame((5.776, -271.0, 125.728), z_axis=(0.0, -1.2192856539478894e-11, 1.0), x_axis=(0.0, 1.0, 1.2192856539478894e-11))),
        ],
        [
            (0, [[1, 2, 3, 4, 5, 6, 7, 8], [9, 10, 11, 12]]),
            (1, [[13, 14, 15, 16, 17, 18, 19, 20], [21, 22, 23, 24]]),
            (2, [[-1, 25, -20, 26]]),
            (3, [[-2, -26, -19, 27]]),
            (4, [[-6, 28, -15, 29]]),
            (5, [[-3, -27, -18, 30]]),
            (6, [[-7, -29, -14, 31]]),
            (7, [[-8, -31, -13, -25]]),
            (8, [[-4, -30, -17, 32]]),
            (9, [[-5, -32, -16, -28]]),
            (10, [[-9, 33, -24, 34]]),
            (11, [[-10, -34, -23, 35]]),
            (12, [[-11, -35, -22, 36]]),
            (13, [[-12, -36, -21, -33]]),
        ],
    ),
        extrude(outline(polyline([(0.0, 0.0), (1.4315306, 0.0), (1.4390415, -2.9920868), (0.0109086, -2.9993294), (0.0, 0.0)])), frame((-4.336, -271.0, 129.528), z_axis=(0.0, 1.0, 1.2192856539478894e-11), x_axis=(0.42472021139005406, 1.1041186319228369e-11, -0.9053246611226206)), (0.0, 0.0, 1.0), 1.0),
        extrude(outline(polyline([(0.4933908, 2.4141097), (1.7898157, 3.022309), (2.1941493, 2.1604399), (5.1636142, 3.5535222), (4.7592806, 4.4153913), (5.9760369, 4.9862153), (8.6568709, -0.728194), (7.4401145, -1.2990179), (7.0459742, -0.4588767), (2.7800844, -2.4601583), (0.4933908, 2.4141097)])), frame((-4.336, -271.0, 129.528), z_axis=(0.0, 1.0, 1.2192856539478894e-11), x_axis=(0.42472021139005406, 1.1041186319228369e-11, -0.9053246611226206)), (0.0, 0.0, 1.0), 1.0),
        extrude(outline(polyline([(0.0, 0.0), (0.96, 0.0), (0.96, 5.352), (0.0, 5.352), (0.0, 6.696), (6.488, 6.696), (6.488, 5.352), (5.504, 5.352), (5.504, -1.304), (0.0, -1.304), (0.0, 0.0)])), frame((10.208, -271.0, 128.696), z_axis=(0.0, 1.0, 1.2192856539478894e-11), x_axis=(1.0, 0.0, 0.0)), (0.0, 0.0, 1.0), 1.0),
        extrude(outline(polyline([(0.0, 0.0), (0.968, 0.0), (0.968, 5.352), (0.0, 5.352), (0.0, 6.696), (3.52, 6.696), (3.52, 5.352), (2.56, 5.352), (2.56, 1.9488753), (6.136, 6.696), (9.728, 1.8807777), (9.728, 5.352), (8.744, 5.352), (8.744, 6.696), (15.128, 6.696), (15.128, 5.352), (14.112, 5.352), (14.112, 0.0), (15.128, 0.0), (15.128, -1.304), (10.256, -1.304), (7.92, 1.696), (5.576, -1.304), (0.0, -1.304), (0.0, 0.0)])), frame((-22.256, -271.0, 128.696), z_axis=(0.0, 1.0, 1.2192856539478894e-11), x_axis=(1.0, 0.0, 0.0)), (0.0, 0.0, 1.0), 1.0),
        extrude(outline(composite_curve([segment(polyline([(-500.0, 27.0), (-501.8150871, 27.0)]), True, "CONTINUOUS"), segment(trimmed(circle_curve(frame_2d((-482.0150871, 31.0)), 20.2), [point((-501.8150871, 27.0))], [point((-501.8150871, 35.0))], False, "CARTESIAN"), True, "CONTINUOUS"), segment(polyline([(-501.8150871, 35.0), (-500.0, 35.0), (-500.0, 27.0)]), True, "CONTINUOUS")], self_intersect=False)), frame((57.0, 0.0, 0.0), z_axis=(1.0, 0.0, 0.0), x_axis=(0.0, 1.0, 0.0)), (0.0, 0.0, 1.0), 21.0),
        extrude(outline(composite_curve([segment(trimmed(circle_curve(frame_2d((-482.0150871, 31.0)), 20.2), [point((-501.8150871, 27.0))], [point((-501.8150871, 35.0))], False, "CARTESIAN"), True, "CONTINUOUS"), segment(polyline([(-501.8150871, 35.0), (-500.0, 35.0), (-500.0, 27.0), (-501.8150871, 27.0)]), True, "CONTINUOUS")], self_intersect=False)), frame((-78.0, 0.0, 0.0), z_axis=(1.0, 0.0, 0.0), x_axis=(0.0, 1.0, 0.0)), (0.0, 0.0, 1.0), 21.0),
        extrude(outline(composite_curve([segment(polyline([(-500.0, 27.0), (-501.8150871, 27.0)]), True, "CONTINUOUS"), segment(trimmed(circle_curve(frame_2d((-482.0150871, 31.0)), 20.2), [point((-501.8150871, 27.0))], [point((-501.8150871, 35.0))], False, "CARTESIAN"), True, "CONTINUOUS"), segment(polyline([(-501.8150871, 35.0), (-500.0, 35.0), (-500.0, 27.0)]), True, "CONTINUOUS")], self_intersect=False)), frame((-56.0, 0.0, 0.0), z_axis=(1.0, 0.0, 0.0), x_axis=(0.0, 1.0, 0.0)), (0.0, 0.0, 1.0), 30.0),
        extrude(outline(composite_curve([segment(polyline([(-500.0, 27.0), (-501.8150871, 27.0)]), True, "CONTINUOUS"), segment(trimmed(circle_curve(frame_2d((-482.0150871, 31.0)), 20.2), [point((-501.8150871, 27.0))], [point((-501.8150871, 35.0))], False, "CARTESIAN"), True, "CONTINUOUS"), segment(polyline([(-501.8150871, 35.0), (-500.0, 35.0), (-500.0, 27.0)]), True, "CONTINUOUS")], self_intersect=False)), frame((-25.0, 0.0, 0.0), z_axis=(1.0, 0.0, 0.0), x_axis=(0.0, 1.0, 0.0)), (0.0, 0.0, 1.0), 50.0),
        extrude(outline(composite_curve([segment(polyline([(-500.0, 27.0), (-501.8150871, 27.0)]), True, "CONTINUOUS"), segment(trimmed(circle_curve(frame_2d((-482.0150871, 31.0)), 20.2), [point((-501.8150871, 27.0))], [point((-501.8150871, 35.0))], False, "CARTESIAN"), True, "CONTINUOUS"), segment(polyline([(-501.8150871, 35.0), (-500.0, 35.0), (-500.0, 27.0)]), True, "CONTINUOUS")], self_intersect=False)), frame((26.0, 0.0, 0.0), z_axis=(1.0, 0.0, 0.0), x_axis=(0.0, 1.0, 0.0)), (0.0, 0.0, 1.0), 30.0),
        faceted_brep([(449.0, 0.0, 62.0), (-449.0, 0.0, 62.0), (-449.0, -500.0, 62.0), (449.0, -500.0, 62.0), (449.0, 0.0, 0.0), (449.0, -500.0, 0.0), (-449.0, -500.0, 0.0), (-449.0, 0.0, 0.0), (-430.5, 0.0, 0.0), (-430.5, -473.0, 0.0), (430.5, -473.0, 0.0), (430.5, 0.0, 0.0), (430.5, 0.0, 2.0), (-430.5, 0.0, 2.0), (430.5, -473.0, 2.0), (430.5, -400.6, 2.0), (430.5, -400.6, 13.7), (430.5, -24.6, 13.7), (430.5, -24.6, 2.0), (-430.5, -473.0, 2.0), (-430.5, -24.6, 2.0), (-430.5, -24.6, 13.7), (-430.5, -400.6, 13.7), (-430.5, -400.6, 2.0)], [[[0, 1, 2, 3]], [[4, 5, 6, 7, 8, 9, 10, 11]], [[1, 0, 4, 11, 12, 13, 8, 7]], [[2, 1, 7, 6]], [[3, 2, 6, 5]], [[0, 3, 5, 4]], [[14, 15, 16, 17, 18, 12, 11, 10]], [[19, 9, 8, 13, 20, 21, 22, 23]], [[14, 10, 9, 19]], [[12, 18, 20, 13]], [[18, 17, 21, 20]], [[17, 16, 22, 21]], [[16, 15, 23, 22]], [[15, 14, 19, 23]]]),
        extrude(outline(polyline([(-8.547125, -112.7), (-4.5372113, -102.654369), (-3.4679009, -102.654369), (0.5420128, -112.7), (-0.7848149, -112.7), (-1.9350593, -109.5607403), (-6.0725055, -109.5607403), (-7.2202973, -112.7), (-8.547125, -112.7)]), holes=[polyline([(-5.6114267, -108.3050364), (-2.3936855, -108.3050364), (-3.2986752, -105.835322), (-4.0025561, -103.9100729), (-4.6279555, -105.6194979), (-5.6114267, -108.3050364)])]), frame((0.0, 0.0, 439.0), z_axis=(0.0, 0.0, 1.0), x_axis=(1.0, 0.0, 0.0)), (0.0, 0.0, 1.0), 1.0),
        extrude(outline(polyline([(1.8835558, -112.7), (1.8835558, -102.654369), (3.1392597, -102.654369), (3.1392597, -111.4442961), (8.1620752, -111.4442961), (8.1620752, -112.7), (1.8835558, -112.7)])), frame((0.0, 0.0, 439.0), z_axis=(0.0, 0.0, 1.0), x_axis=(1.0, 0.0, 0.0)), (0.0, 0.0, 1.0), 1.0),
        extrude(outline(polyline([(384.8, 104.3772603), (394.845631, 104.3772603), (394.845631, 97.156963), (393.5899271, 97.156963), (393.5899271, 103.1215564), (390.6076304, 103.1215564), (390.6076304, 97.470889), (389.3519266, 97.470889), (389.3519266, 103.1215564), (386.0557039, 103.1215564), (386.0557039, 97.0), (384.8, 97.0), (384.8, 104.3772603)])), frame((0.0, -164.0, 0.0), z_axis=(0.0, 1.0, 0.0), x_axis=(0.0, 0.0, 1.0)), (0.0, 0.0, 1.0), 1.0),
        extrude(outline(polyline([(384.8, 95.1164442), (394.845631, 95.1164442), (394.845631, 93.8607403), (386.0557039, 93.8607403), (386.0557039, 88.8379248), (384.8, 88.8379248), (384.8, 95.1164442)])), frame((0.0, -164.0, 0.0), z_axis=(0.0, 1.0, 0.0), x_axis=(0.0, 0.0, 1.0)), (0.0, 0.0, 1.0), 1.0),
        extrude(outline(composite_curve([segment(trimmed(circle_curve(frame_2d((389.8, 97.0)), 7.5369395), [point((389.8, 104.5369395))], [point((389.8, 89.4630605))], False, "CARTESIAN"), True, "CONTINUOUS"), segment(trimmed(circle_curve(frame_2d((389.8, 97.0)), 7.5369395), [point((389.8, 89.4630605))], [point((389.8, 104.5369395))], False, "CARTESIAN"), True, "CONTINUOUS")], self_intersect=False)), frame((0.0, -194.0, 0.0), z_axis=(0.0, 1.0, 0.0), x_axis=(0.0, 0.0, 1.0)), (0.0, 0.0, 1.0), 30.0),
        extrude(outline(polyline([(124.5, -263.0), (-123.0, -263.0), (-123.0, -194.0), (124.5, -194.0), (124.5, -263.0)])), frame((0.0, 0.0, 379.8), z_axis=(0.0, 0.0, 1.0), x_axis=(1.0, 0.0, 0.0)), (0.0, 0.0, 1.0), 120.2),
        extrude(outline(composite_curve([segment(trimmed(circle_curve(frame_2d((0.0, -107.7)), 75.0), [point((-75.0, -107.7))], [point((75.0, -107.7))], False, "CARTESIAN"), True, "CONTINUOUS"), segment(trimmed(circle_curve(frame_2d((0.0, -107.7)), 75.0), [point((75.0, -107.7))], [point((-75.0, -107.7))], False, "CARTESIAN"), True, "CONTINUOUS")], self_intersect=False), holes=[composite_curve([segment(trimmed(circle_curve(frame_2d((0.0, -107.7)), 72.5), [point((-72.5, -107.7))], [point((72.5, -107.7))], True, "CARTESIAN"), True, "CONTINUOUS"), segment(trimmed(circle_curve(frame_2d((0.0, -107.7)), 72.5), [point((72.5, -107.7))], [point((-72.5, -107.7))], True, "CARTESIAN"), True, "CONTINUOUS")], self_intersect=False)]), frame((0.0, 0.0, 379.8), z_axis=(0.0, 0.0, 1.0), x_axis=(1.0, 0.0, 0.0)), (0.0, 0.0, 1.0), 59.2),
        extrude(outline(polyline([(141.25, -4.0), (141.25, -264.5), (-141.25, -264.5), (-141.25, -4.0), (141.25, -4.0)])), frame((0.0, 0.0, 85.7), z_axis=(0.0, 0.0, 1.0), x_axis=(1.0, 0.0, 0.0)), (0.0, 0.0, 1.0), 294.1),
        extrude(outline(polyline([(142.2, -4.0), (142.2, -267.0), (-142.2, -267.0), (-142.2, -4.0), (142.2, -4.0)])), frame((0.0, 0.0, 62.0), z_axis=(0.0, 0.0, 1.0), x_axis=(1.0, 0.0, 0.0)), (0.0, 0.0, 1.0), 23.7),
    ])


if __name__ == "__main__":
    model = new_model("IFC4")
    model_context = context("Model", 3, world=origin())
    ifc_project = project(units=[si_unit("LENGTHUNIT", "METRE", prefix="MILLI")], contexts=[model_context])
    site = spatial("IfcSite", under=ifc_project)
    building = spatial("IfcBuilding", under=site)
    placement = place(None, origin())
    specialty_equipment_shape = specialty_equipment_3feef1e1(model_context)
    element("IfcBuildingElementProxy", 1, Name="Specialty Equipment", at=placement, inside=building, context=model_context, shape_type="MappedRepresentation", body=[
        mapped(specialty_equipment_shape, transform((0.0, 0.0, 0.0), x_axis=(1.0, 0.0, 0.0), y_axis=(0.0, 1.0, 0.0), z_axis=(0.0, 0.0, 1.0))),
    ])
    save(model, "model.ifc")
